VERSION 5.7 ;
BUSBITCHARS "[]" ;
DIVIDERCHAR "/" ;
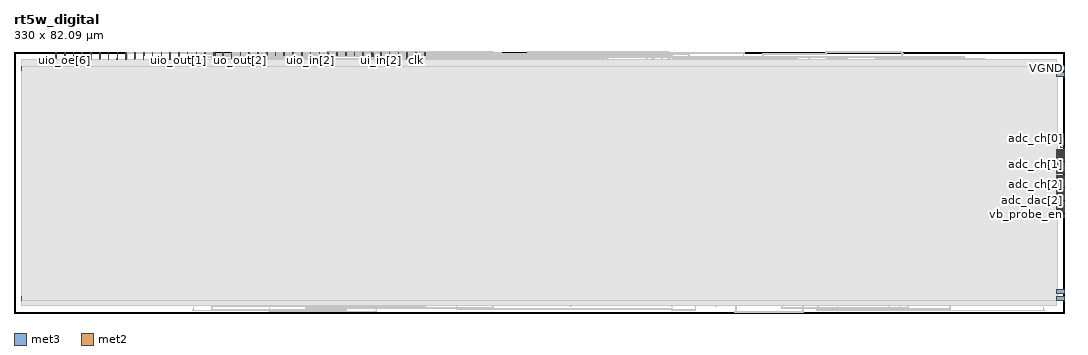
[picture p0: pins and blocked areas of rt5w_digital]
MACRO rt5w_digital
  CLASS BLOCK ;
  FOREIGN rt5w_digital ;
  ORIGIN 0.000 0.000 ;
  SIZE 330.000 BY 82.090 ;
  SYMMETRY X Y ;
  PIN VGND
    DIRECTION INOUT ;
    USE SIGNAL ;
    PORT
      LAYER met3 ;
        RECT 2.340 4.060 2.500 5.260 ;
        RECT 327.500 4.060 330.000 5.260 ;
        RECT 2.340 76.340 2.500 77.540 ;
        RECT 327.500 76.340 330.000 77.540 ;
    END
  END VGND
  PIN VPWR
    DIRECTION INOUT ;
    USE SIGNAL ;
    PORT
      LAYER met3 ;
        RECT 327.500 6.060 330.000 7.260 ;
        RECT 327.500 74.340 330.000 75.540 ;
    END
  END VPWR
  PIN adc_ch[0]
    DIRECTION INOUT ;
    USE SIGNAL ;
    PORT
      LAYER met3 ;
        RECT 329.050 51.870 330.000 52.170 ;
        RECT 328.750 51.870 329.050 52.850 ;
        RECT 327.500 54.590 329.670 54.890 ;
        RECT 329.670 52.850 329.970 54.890 ;
        RECT 329.050 52.550 329.970 52.850 ;
    END
  END adc_ch[0]
  PIN adc_ch[1]
    DIRECTION INOUT ;
    USE SIGNAL ;
    PORT
      LAYER met3 ;
        RECT 327.500 46.430 330.000 46.730 ;
    END
  END adc_ch[1]
  PIN adc_ch[2]
    DIRECTION INOUT ;
    USE SIGNAL ;
    PORT
      LAYER met3 ;
        RECT 327.500 40.310 330.000 40.610 ;
    END
  END adc_ch[2]
  PIN adc_ch[3]
    DIRECTION INOUT ;
    USE SIGNAL ;
    PORT
      LAYER met3 ;
        RECT 327.500 39.630 330.000 39.930 ;
    END
  END adc_ch[3]
  PIN adc_cmp
    DIRECTION INOUT ;
    USE SIGNAL ;
    PORT
      LAYER met3 ;
        RECT 327.500 40.990 330.000 41.290 ;
    END
  END adc_cmp
  PIN adc_dac[0]
    DIRECTION INOUT ;
    USE SIGNAL ;
    PORT
      LAYER met3 ;
        RECT 327.500 41.670 330.000 41.970 ;
    END
  END adc_dac[0]
  PIN adc_dac[1]
    DIRECTION INOUT ;
    USE SIGNAL ;
    PORT
      LAYER met3 ;
        RECT 327.500 47.110 330.000 47.410 ;
    END
  END adc_dac[1]
  PIN adc_dac[2]
    DIRECTION INOUT ;
    USE SIGNAL ;
    PORT
      LAYER met3 ;
        RECT 327.500 37.590 330.000 37.890 ;
    END
  END adc_dac[2]
  PIN adc_dac[3]
    DIRECTION INOUT ;
    USE SIGNAL ;
    PORT
      LAYER met3 ;
        RECT 327.500 36.910 330.000 37.210 ;
    END
  END adc_dac[3]
  PIN adc_dac[4]
    DIRECTION INOUT ;
    USE SIGNAL ;
    PORT
      LAYER met3 ;
        RECT 327.500 49.830 330.000 50.130 ;
    END
  END adc_dac[4]
  PIN adc_dac[5]
    DIRECTION INOUT ;
    USE SIGNAL ;
    PORT
      LAYER met3 ;
        RECT 327.500 36.230 330.000 36.530 ;
    END
  END adc_dac[5]
  PIN adc_dac[6]
    DIRECTION INOUT ;
    USE SIGNAL ;
    PORT
      LAYER met3 ;
        RECT 327.500 47.790 330.000 48.090 ;
    END
  END adc_dac[6]
  PIN adc_dac[7]
    DIRECTION INOUT ;
    USE SIGNAL ;
    PORT
      LAYER met3 ;
        RECT 327.500 34.870 330.000 35.170 ;
    END
  END adc_dac[7]
  PIN adc_lat
    DIRECTION INOUT ;
    USE SIGNAL ;
    PORT
      LAYER met3 ;
        RECT 327.500 43.030 330.000 43.330 ;
    END
  END adc_lat
  PIN adc_rst
    DIRECTION INOUT ;
    USE SIGNAL ;
    PORT
      LAYER met3 ;
        RECT 327.500 34.190 330.000 34.490 ;
    END
  END adc_rst
  PIN bias_en
    DIRECTION INOUT ;
    USE SIGNAL ;
    PORT
      LAYER met3 ;
        RECT 327.500 33.510 330.000 33.810 ;
    END
  END bias_en
  PIN cfg_sclk
    DIRECTION INOUT ;
    USE SIGNAL ;
    PORT
      LAYER met3 ;
        RECT 327.500 32.830 330.000 33.130 ;
    END
  END cfg_sclk
  PIN cfg_sdat
    DIRECTION INOUT ;
    USE SIGNAL ;
    PORT
      LAYER met3 ;
        RECT 327.500 43.710 330.000 44.010 ;
    END
  END cfg_sdat
  PIN clk
    DIRECTION INOUT ;
    USE SIGNAL ;
    PORT
      LAYER met2 ;
        RECT 126.240 81.000 126.340 82.000 ;
        RECT 126.270 79.800 126.340 81.000 ;
        RECT 126.200 79.590 126.340 79.800 ;
        RECT 126.340 79.660 126.410 81.000 ;
        RECT 126.340 81.000 126.440 82.000 ;
    END
  END clk
  PIN ena
    DIRECTION INOUT ;
    USE SIGNAL ;
    PORT
      LAYER met2 ;
        RECT 129.000 81.000 129.200 82.000 ;
    END
  END ena
  PIN pump_dn[0]
    DIRECTION INOUT ;
    USE SIGNAL ;
    PORT
      LAYER met3 ;
        RECT 327.500 48.470 330.000 48.770 ;
    END
  END pump_dn[0]
  PIN pump_dn[1]
    DIRECTION INOUT ;
    USE SIGNAL ;
    PORT
      LAYER met3 ;
        RECT 327.500 51.190 330.000 51.490 ;
    END
  END pump_dn[1]
  PIN pump_dn[2]
    DIRECTION INOUT ;
    USE SIGNAL ;
    PORT
      LAYER met3 ;
        RECT 327.500 38.270 330.000 38.570 ;
    END
  END pump_dn[2]
  PIN pump_dn[3]
    DIRECTION INOUT ;
    USE SIGNAL ;
    PORT
      LAYER met3 ;
        RECT 327.500 44.390 330.000 44.690 ;
    END
  END pump_dn[3]
  PIN pump_up[0]
    DIRECTION INOUT ;
    USE SIGNAL ;
    PORT
      LAYER met3 ;
        RECT 327.500 32.150 330.000 32.450 ;
    END
  END pump_up[0]
  PIN pump_up[1]
    DIRECTION INOUT ;
    USE SIGNAL ;
    PORT
      LAYER met3 ;
        RECT 327.500 50.510 330.000 50.810 ;
    END
  END pump_up[1]
  PIN pump_up[2]
    DIRECTION INOUT ;
    USE SIGNAL ;
    PORT
      LAYER met3 ;
        RECT 327.500 45.750 330.000 46.050 ;
    END
  END pump_up[2]
  PIN pump_up[3]
    DIRECTION INOUT ;
    USE SIGNAL ;
    PORT
      LAYER met3 ;
        RECT 327.500 45.070 330.000 45.370 ;
    END
  END pump_up[3]
  PIN rst_n
    DIRECTION INOUT ;
    USE SIGNAL ;
    PORT
      LAYER met2 ;
        RECT 123.480 81.000 123.580 82.000 ;
        RECT 123.510 79.800 123.580 81.000 ;
        RECT 123.440 79.590 123.580 79.800 ;
        RECT 123.580 79.660 123.650 81.000 ;
        RECT 123.580 81.000 123.680 82.000 ;
    END
  END rst_n
  PIN ui_in[0]
    DIRECTION INOUT ;
    USE SIGNAL ;
    PORT
      LAYER met2 ;
        RECT 120.720 81.000 120.820 82.000 ;
        RECT 120.750 79.800 120.820 81.000 ;
        RECT 120.680 79.590 120.820 79.800 ;
        RECT 120.820 79.660 120.890 81.000 ;
        RECT 120.820 81.000 120.920 82.000 ;
    END
  END ui_in[0]
  PIN ui_in[1]
    DIRECTION INOUT ;
    USE SIGNAL ;
    PORT
      LAYER met2 ;
        RECT 117.960 81.000 118.060 82.000 ;
        RECT 117.990 79.800 118.060 81.000 ;
        RECT 117.920 79.590 118.060 79.800 ;
        RECT 118.060 79.660 118.130 81.000 ;
        RECT 118.060 81.000 118.160 82.000 ;
    END
  END ui_in[1]
  PIN ui_in[2]
    DIRECTION INOUT ;
    USE SIGNAL ;
    PORT
      LAYER met2 ;
        RECT 115.200 81.000 115.300 82.000 ;
        RECT 115.230 79.800 115.300 81.000 ;
        RECT 115.160 79.590 115.300 79.800 ;
        RECT 115.300 79.660 115.370 81.000 ;
        RECT 115.300 81.000 115.400 82.000 ;
    END
  END ui_in[2]
  PIN ui_in[3]
    DIRECTION INOUT ;
    USE SIGNAL ;
    PORT
      LAYER met2 ;
        RECT 112.800 81.270 113.060 81.590 ;
        RECT 112.860 80.820 113.000 81.270 ;
        RECT 112.470 80.680 113.000 80.820 ;
        RECT 112.440 81.000 112.640 82.000 ;
        RECT 112.470 80.820 112.610 81.000 ;
    END
  END ui_in[3]
  PIN ui_in[4]
    DIRECTION INOUT ;
    USE SIGNAL ;
    PORT
      LAYER met2 ;
        RECT 109.680 81.000 109.880 82.000 ;
    END
  END ui_in[4]
  PIN ui_in[5]
    DIRECTION INOUT ;
    USE SIGNAL ;
    PORT
      LAYER met2 ;
        RECT 106.920 81.000 107.120 82.000 ;
    END
  END ui_in[5]
  PIN ui_in[6]
    DIRECTION INOUT ;
    USE SIGNAL ;
    PORT
      LAYER met2 ;
        RECT 104.160 81.000 104.360 82.000 ;
    END
  END ui_in[6]
  PIN ui_in[7]
    DIRECTION INOUT ;
    USE SIGNAL ;
    PORT
      LAYER met2 ;
        RECT 101.400 81.000 101.600 82.000 ;
    END
  END ui_in[7]
  PIN uio_in[0]
    DIRECTION INOUT ;
    USE SIGNAL ;
    PORT
      LAYER met2 ;
        RECT 98.640 81.000 98.840 82.000 ;
    END
  END uio_in[0]
  PIN uio_in[1]
    DIRECTION INOUT ;
    USE SIGNAL ;
    PORT
      LAYER met2 ;
        RECT 95.880 81.000 96.080 82.000 ;
    END
  END uio_in[1]
  PIN uio_in[2]
    DIRECTION INOUT ;
    USE SIGNAL ;
    PORT
      LAYER met2 ;
        RECT 93.120 81.000 93.320 82.000 ;
    END
  END uio_in[2]
  PIN uio_in[3]
    DIRECTION INOUT ;
    USE SIGNAL ;
    PORT
      LAYER met2 ;
        RECT 90.360 81.000 90.560 82.000 ;
    END
  END uio_in[3]
  PIN uio_in[4]
    DIRECTION INOUT ;
    USE SIGNAL ;
    PORT
      LAYER met2 ;
        RECT 87.600 81.000 87.800 82.000 ;
    END
  END uio_in[4]
  PIN uio_in[5]
    DIRECTION INOUT ;
    USE SIGNAL ;
    PORT
      LAYER met2 ;
        RECT 84.840 81.000 85.040 82.000 ;
    END
  END uio_in[5]
  PIN uio_in[6]
    DIRECTION INOUT ;
    USE SIGNAL ;
    PORT
      LAYER met2 ;
        RECT 82.080 81.000 82.280 82.000 ;
    END
  END uio_in[6]
  PIN uio_in[7]
    DIRECTION INOUT ;
    USE SIGNAL ;
    PORT
      LAYER met2 ;
        RECT 79.320 81.000 79.520 82.000 ;
    END
  END uio_in[7]
  PIN uio_oe[0]
    DIRECTION INOUT ;
    USE SIGNAL ;
    PORT
      LAYER met2 ;
        RECT 32.400 81.000 32.500 82.000 ;
        RECT 32.430 79.970 32.500 81.000 ;
        RECT 32.360 79.590 32.500 79.970 ;
        RECT 32.500 79.830 32.570 81.000 ;
        RECT 32.500 81.000 32.600 82.000 ;
    END
  END uio_oe[0]
  PIN uio_oe[1]
    DIRECTION INOUT ;
    USE SIGNAL ;
    PORT
      LAYER met2 ;
        RECT 29.640 81.000 29.740 82.000 ;
        RECT 29.670 79.970 29.740 81.000 ;
        RECT 29.600 79.590 29.740 79.970 ;
        RECT 29.740 79.830 29.810 81.000 ;
        RECT 29.740 81.000 29.840 82.000 ;
    END
  END uio_oe[1]
  PIN uio_oe[2]
    DIRECTION INOUT ;
    USE SIGNAL ;
    PORT
      LAYER met2 ;
        RECT 26.880 81.000 26.980 82.000 ;
        RECT 26.910 79.970 26.980 81.000 ;
        RECT 26.840 79.590 26.980 79.970 ;
        RECT 26.980 79.830 27.050 81.000 ;
        RECT 26.980 81.000 27.080 82.000 ;
    END
  END uio_oe[2]
  PIN uio_oe[3]
    DIRECTION INOUT ;
    USE SIGNAL ;
    PORT
      LAYER met2 ;
        RECT 24.120 81.000 24.220 82.000 ;
        RECT 24.150 79.970 24.220 81.000 ;
        RECT 24.080 79.590 24.220 79.970 ;
        RECT 24.220 79.830 24.290 81.000 ;
        RECT 24.220 81.000 24.320 82.000 ;
    END
  END uio_oe[3]
  PIN uio_oe[4]
    DIRECTION INOUT ;
    USE SIGNAL ;
    PORT
      LAYER met2 ;
        RECT 21.360 81.000 21.460 82.000 ;
        RECT 21.390 79.970 21.460 81.000 ;
        RECT 21.320 79.590 21.460 79.970 ;
        RECT 21.460 79.830 21.530 81.000 ;
        RECT 21.460 81.000 21.560 82.000 ;
    END
  END uio_oe[4]
  PIN uio_oe[5]
    DIRECTION INOUT ;
    USE SIGNAL ;
    PORT
      LAYER met2 ;
        RECT 18.600 81.000 18.700 82.000 ;
        RECT 18.630 79.970 18.700 81.000 ;
        RECT 18.560 79.590 18.700 79.970 ;
        RECT 18.700 79.830 18.770 81.000 ;
        RECT 18.700 81.000 18.800 82.000 ;
    END
  END uio_oe[5]
  PIN uio_oe[6]
    DIRECTION INOUT ;
    USE SIGNAL ;
    PORT
      LAYER met2 ;
        RECT 15.840 81.000 15.940 82.000 ;
        RECT 15.870 79.970 15.940 81.000 ;
        RECT 15.800 79.590 15.940 79.970 ;
        RECT 15.940 79.830 16.010 81.000 ;
        RECT 15.940 81.000 16.040 82.000 ;
    END
  END uio_oe[6]
  PIN uio_oe[7]
    DIRECTION INOUT ;
    USE SIGNAL ;
    PORT
      LAYER met2 ;
        RECT 13.080 81.000 13.180 82.000 ;
        RECT 13.110 79.970 13.180 81.000 ;
        RECT 13.040 79.590 13.180 79.970 ;
        RECT 13.180 79.830 13.250 81.000 ;
        RECT 13.180 81.000 13.280 82.000 ;
    END
  END uio_oe[7]
  PIN uio_out[0]
    DIRECTION INOUT ;
    USE SIGNAL ;
    PORT
      LAYER met2 ;
        RECT 54.480 81.000 54.580 82.000 ;
        RECT 54.510 79.800 54.580 81.000 ;
        RECT 54.440 79.590 54.580 79.800 ;
        RECT 54.580 79.660 54.650 81.000 ;
        RECT 54.580 81.000 54.680 82.000 ;
    END
  END uio_out[0]
  PIN uio_out[1]
    DIRECTION INOUT ;
    USE SIGNAL ;
    PORT
      LAYER met2 ;
        RECT 51.720 81.000 51.820 82.000 ;
        RECT 51.750 79.970 51.820 81.000 ;
        RECT 51.680 79.590 51.820 79.970 ;
        RECT 51.820 79.830 51.890 81.000 ;
        RECT 51.820 81.000 51.920 82.000 ;
    END
  END uio_out[1]
  PIN uio_out[2]
    DIRECTION INOUT ;
    USE SIGNAL ;
    PORT
      LAYER met2 ;
        RECT 48.960 81.000 49.060 82.000 ;
        RECT 48.990 79.970 49.060 81.000 ;
        RECT 48.920 79.590 49.060 79.970 ;
        RECT 49.060 79.830 49.130 81.000 ;
        RECT 49.060 81.000 49.160 82.000 ;
    END
  END uio_out[2]
  PIN uio_out[3]
    DIRECTION INOUT ;
    USE SIGNAL ;
    PORT
      LAYER met2 ;
        RECT 46.200 81.000 46.300 82.000 ;
        RECT 46.230 79.970 46.300 81.000 ;
        RECT 46.160 79.590 46.300 79.970 ;
        RECT 46.300 79.830 46.370 81.000 ;
        RECT 46.300 81.000 46.400 82.000 ;
    END
  END uio_out[3]
  PIN uio_out[4]
    DIRECTION INOUT ;
    USE SIGNAL ;
    PORT
      LAYER met2 ;
        RECT 43.440 81.000 43.540 82.000 ;
        RECT 43.470 79.970 43.540 81.000 ;
        RECT 43.400 79.590 43.540 79.970 ;
        RECT 43.540 79.830 43.610 81.000 ;
        RECT 43.540 81.000 43.640 82.000 ;
    END
  END uio_out[4]
  PIN uio_out[5]
    DIRECTION INOUT ;
    USE SIGNAL ;
    PORT
      LAYER met2 ;
        RECT 40.680 81.000 40.780 82.000 ;
        RECT 40.710 79.970 40.780 81.000 ;
        RECT 40.640 79.590 40.780 79.970 ;
        RECT 40.780 79.830 40.850 81.000 ;
        RECT 40.780 81.000 40.880 82.000 ;
    END
  END uio_out[5]
  PIN uio_out[6]
    DIRECTION INOUT ;
    USE SIGNAL ;
    PORT
      LAYER met2 ;
        RECT 37.920 81.000 38.020 82.000 ;
        RECT 37.950 79.970 38.020 81.000 ;
        RECT 37.880 79.590 38.020 79.970 ;
        RECT 38.020 79.830 38.090 81.000 ;
        RECT 38.020 81.000 38.120 82.000 ;
    END
  END uio_out[6]
  PIN uio_out[7]
    DIRECTION INOUT ;
    USE SIGNAL ;
    PORT
      LAYER met2 ;
        RECT 35.160 81.000 35.260 82.000 ;
        RECT 35.190 79.970 35.260 81.000 ;
        RECT 35.120 79.590 35.260 79.970 ;
        RECT 35.260 79.830 35.330 81.000 ;
        RECT 35.260 81.000 35.360 82.000 ;
    END
  END uio_out[7]
  PIN uo_out[0]
    DIRECTION INOUT ;
    USE SIGNAL ;
    PORT
      LAYER met2 ;
        RECT 76.560 81.000 76.660 82.000 ;
        RECT 76.590 79.800 76.660 81.000 ;
        RECT 76.520 79.590 76.660 79.800 ;
        RECT 76.660 79.660 76.730 81.000 ;
        RECT 76.660 81.000 76.760 82.000 ;
    END
  END uo_out[0]
  PIN uo_out[1]
    DIRECTION INOUT ;
    USE SIGNAL ;
    PORT
      LAYER met2 ;
        RECT 73.800 81.000 74.000 82.000 ;
        RECT 73.830 80.765 73.970 81.000 ;
        RECT 73.760 80.395 74.040 80.765 ;
    END
  END uo_out[1]
  PIN uo_out[2]
    DIRECTION INOUT ;
    USE SIGNAL ;
    PORT
      LAYER met2 ;
        RECT 71.040 81.000 71.140 82.000 ;
        RECT 71.070 79.800 71.140 81.000 ;
        RECT 71.000 79.590 71.140 79.800 ;
        RECT 71.140 79.660 71.210 81.000 ;
        RECT 71.140 81.000 71.240 82.000 ;
    END
  END uo_out[2]
  PIN uo_out[3]
    DIRECTION INOUT ;
    USE SIGNAL ;
    PORT
      LAYER met2 ;
        RECT 68.280 81.000 68.480 82.000 ;
        RECT 68.310 80.230 68.450 81.000 ;
        RECT 68.250 79.910 68.510 80.230 ;
    END
  END uo_out[3]
  PIN uo_out[4]
    DIRECTION INOUT ;
    USE SIGNAL ;
    PORT
      LAYER met2 ;
        RECT 65.520 81.000 65.720 82.000 ;
        RECT 65.550 80.085 65.690 81.000 ;
        RECT 65.480 79.715 65.760 80.085 ;
    END
  END uo_out[4]
  PIN uo_out[5]
    DIRECTION INOUT ;
    USE SIGNAL ;
    PORT
      LAYER met2 ;
        RECT 63.120 81.270 63.380 81.590 ;
        RECT 63.180 80.650 63.320 81.270 ;
        RECT 62.790 80.510 63.320 80.650 ;
        RECT 62.760 81.000 62.960 82.000 ;
        RECT 62.790 80.650 62.930 81.000 ;
    END
  END uo_out[5]
  PIN uo_out[6]
    DIRECTION INOUT ;
    USE SIGNAL ;
    PORT
      LAYER met2 ;
        RECT 60.000 81.000 60.200 82.000 ;
        RECT 60.030 80.570 60.170 81.000 ;
        RECT 59.970 80.250 60.230 80.570 ;
    END
  END uo_out[6]
  PIN uo_out[7]
    DIRECTION INOUT ;
    USE SIGNAL ;
    PORT
      LAYER met2 ;
        RECT 57.240 81.000 57.340 82.000 ;
        RECT 57.270 79.970 57.340 81.000 ;
        RECT 57.200 79.590 57.340 79.970 ;
        RECT 57.340 79.830 57.410 81.000 ;
        RECT 57.340 81.000 57.440 82.000 ;
    END
  END uo_out[7]
  PIN vb_probe_en
    DIRECTION INOUT ;
    USE SIGNAL ;
    PORT
      LAYER met3 ;
        RECT 327.500 30.790 330.000 31.090 ;
    END
  END vb_probe_en
  PIN wsel_a[0]
    DIRECTION INOUT ;
    USE SIGNAL ;
    PORT
      LAYER met3 ;
        RECT 327.500 30.110 330.000 30.410 ;
    END
  END wsel_a[0]
  PIN wsel_a[1]
    DIRECTION INOUT ;
    USE SIGNAL ;
    PORT
      LAYER met3 ;
        RECT 327.500 42.350 330.000 42.650 ;
    END
  END wsel_a[1]
  PIN wsel_a[2]
    DIRECTION INOUT ;
    USE SIGNAL ;
    PORT
      LAYER met3 ;
        RECT 327.500 49.150 330.000 49.450 ;
    END
  END wsel_a[2]
  PIN wsel_a[3]
    DIRECTION INOUT ;
    USE SIGNAL ;
    PORT
      LAYER met3 ;
        RECT 327.500 31.470 330.000 31.770 ;
    END
  END wsel_a[3]
  PIN wsel_a[4]
    DIRECTION INOUT ;
    USE SIGNAL ;
    PORT
      LAYER met3 ;
        RECT 327.500 38.950 330.000 39.250 ;
    END
  END wsel_a[4]
  PIN wsel_e
    DIRECTION INOUT ;
    USE SIGNAL ;
    PORT
      LAYER met3 ;
        RECT 327.500 35.550 330.000 35.850 ;
    END
  END wsel_e
  OBS
    LAYER li1 ;
      RECT 2.500 2.500 327.500 79.590 ;
    LAYER met1 ;
      RECT 138.990 1.120 206.610 1.260 ;
      RECT 132.550 79.660 173.030 79.800 ;
      RECT 134.390 80.000 182.690 80.140 ;
      RECT 2.500 2.500 327.500 79.590 ;
      RECT 153.110 80.340 217.280 80.480 ;
      RECT 85.630 81.020 200.170 81.160 ;
      RECT 112.770 81.360 201.090 81.500 ;
      RECT 173.030 79.600 173.350 79.860 ;
      RECT 182.690 79.940 183.010 80.200 ;
      RECT 173.490 79.600 173.810 79.660 ;
      RECT 217.280 80.000 241.570 80.140 ;
      RECT 241.570 79.940 241.890 80.200 ;
      RECT 173.490 79.800 173.810 79.860 ;
      RECT 217.280 80.140 217.420 80.480 ;
      RECT 234.670 80.280 234.990 80.340 ;
      RECT 234.670 80.480 234.990 80.540 ;
      RECT 234.670 80.340 255.370 80.480 ;
      RECT 255.370 80.280 255.690 80.540 ;
      RECT 165.210 80.620 165.530 80.680 ;
      RECT 165.210 80.820 165.530 80.880 ;
      RECT 165.210 80.680 205.230 80.820 ;
      RECT 205.230 80.620 205.550 80.880 ;
      RECT 173.490 79.660 203.390 79.800 ;
      RECT 200.170 80.960 200.490 81.220 ;
      RECT 200.630 80.960 200.950 81.020 ;
      RECT 200.630 81.160 200.950 81.220 ;
      RECT 200.630 81.020 205.690 81.160 ;
      RECT 205.690 80.960 206.010 81.220 ;
      RECT 203.390 79.600 203.710 79.860 ;
      RECT 201.090 81.300 201.410 81.560 ;
      RECT 202.010 81.300 202.330 81.360 ;
      RECT 202.010 81.500 202.330 81.560 ;
      RECT 202.010 81.360 206.150 81.500 ;
      RECT 206.150 81.300 206.470 81.560 ;
      RECT 188.210 81.640 188.530 81.700 ;
      RECT 188.210 81.840 188.530 81.900 ;
      RECT 188.210 81.700 229.150 81.840 ;
      RECT 229.150 81.640 229.470 81.900 ;
      RECT 87.930 80.340 98.050 80.480 ;
      RECT 98.050 80.280 98.370 80.540 ;
      RECT 111.850 80.280 112.170 80.340 ;
      RECT 111.850 80.480 112.170 80.540 ;
      RECT 111.850 80.340 127.030 80.480 ;
      RECT 127.030 80.280 127.350 80.540 ;
      RECT 127.490 80.280 127.810 80.340 ;
      RECT 127.490 80.480 127.810 80.540 ;
      RECT 127.490 80.340 129.790 80.480 ;
      RECT 129.790 80.280 130.110 80.540 ;
      RECT 68.220 80.140 68.540 80.200 ;
      RECT 131.260 80.000 131.400 80.340 ;
      RECT 68.220 79.940 68.540 80.140 ;
      RECT 68.540 80.000 131.260 80.140 ;
      RECT 131.260 80.340 152.330 80.480 ;
      RECT 152.330 80.280 152.650 80.540 ;
      RECT 132.550 79.800 132.870 79.860 ;
      RECT 82.410 79.600 82.730 79.660 ;
      RECT 152.790 80.280 153.110 80.340 ;
      RECT 82.410 79.800 82.730 79.860 ;
      RECT 152.790 80.340 153.110 80.540 ;
      RECT 82.410 79.660 106.330 79.800 ;
      RECT 106.330 79.600 106.650 79.860 ;
      RECT 106.790 79.600 107.110 79.660 ;
      RECT 106.790 79.800 107.110 79.860 ;
      RECT 112.310 79.800 112.630 79.860 ;
      RECT 110.010 80.620 110.330 80.680 ;
      RECT 110.010 80.820 110.330 80.880 ;
      RECT 110.010 80.680 160.150 80.820 ;
      RECT 160.150 80.620 160.470 80.880 ;
      RECT 132.220 79.660 132.360 80.000 ;
      RECT 112.310 79.600 112.630 79.800 ;
      RECT 112.630 79.660 132.220 79.800 ;
      RECT 132.220 80.000 133.930 80.140 ;
      RECT 85.630 80.960 85.950 81.020 ;
      RECT 85.630 81.160 85.950 81.220 ;
      RECT 133.930 79.940 134.250 80.200 ;
      RECT 134.390 79.940 134.710 80.000 ;
      RECT 134.390 80.140 134.710 80.200 ;
      RECT 106.790 79.660 110.010 79.800 ;
      RECT 110.010 79.600 110.330 79.860 ;
      RECT 59.940 80.280 60.260 80.340 ;
      RECT 57.570 81.300 57.890 81.360 ;
      RECT 57.570 81.500 57.890 81.560 ;
      RECT 57.570 81.360 62.170 81.500 ;
      RECT 62.170 81.300 62.490 81.560 ;
      RECT 63.090 81.300 63.410 81.360 ;
      RECT 63.090 81.500 63.410 81.560 ;
      RECT 63.090 81.360 111.850 81.500 ;
      RECT 111.850 81.300 112.170 81.560 ;
      RECT 112.770 81.300 113.090 81.360 ;
      RECT 112.770 81.500 113.090 81.560 ;
      RECT 60.260 80.340 62.025 80.480 ;
      RECT 59.940 80.340 60.260 80.540 ;
      RECT 62.025 79.590 62.165 80.480 ;
      RECT 132.550 79.600 132.870 79.660 ;
      RECT 75.970 80.280 76.290 80.340 ;
      RECT 75.970 80.480 76.290 80.540 ;
      RECT 62.790 80.680 109.090 80.820 ;
      RECT 109.090 80.620 109.410 80.880 ;
      RECT 35.490 81.640 35.810 81.700 ;
      RECT 35.810 81.700 62.790 81.840 ;
      RECT 35.490 81.700 35.810 81.900 ;
      RECT 62.790 80.820 62.930 81.840 ;
      RECT 68.610 81.640 68.930 81.700 ;
      RECT 68.610 81.840 68.930 81.900 ;
      RECT 68.610 81.700 88.850 81.840 ;
      RECT 88.850 81.640 89.170 81.900 ;
      RECT 89.310 81.640 89.630 81.700 ;
      RECT 89.310 81.840 89.630 81.900 ;
      RECT 89.310 81.700 132.550 81.840 ;
      RECT 132.550 81.640 132.870 81.900 ;
      RECT 133.010 81.640 133.330 81.700 ;
      RECT 133.010 81.840 133.330 81.900 ;
      RECT 133.010 81.700 152.790 81.840 ;
      RECT 152.790 81.640 153.110 81.900 ;
      RECT 75.970 80.340 86.550 80.480 ;
      RECT 86.550 80.280 86.870 80.540 ;
      RECT 87.930 80.280 88.250 80.340 ;
      RECT 87.930 80.480 88.250 80.540 ;
      RECT 56.190 0.920 56.510 0.980 ;
      RECT 56.190 0.780 96.670 0.920 ;
      RECT 96.670 0.720 96.990 0.980 ;
      RECT 138.990 1.060 139.310 1.120 ;
      RECT 138.990 1.260 139.310 1.320 ;
      RECT 80.110 0.380 80.430 0.440 ;
      RECT 62.170 2.080 62.490 2.140 ;
      RECT 62.170 2.280 62.490 2.340 ;
      RECT 85.170 2.420 85.490 2.480 ;
      RECT 62.170 2.140 128.870 2.280 ;
      RECT 85.170 2.480 138.530 2.500 ;
      RECT 138.530 2.420 138.850 2.500 ;
      RECT 128.870 2.080 129.190 2.340 ;
      RECT 80.110 0.580 80.430 0.640 ;
      RECT 80.110 0.440 113.690 0.580 ;
      RECT 113.690 0.380 114.010 0.640 ;
      RECT 56.190 0.720 56.510 0.780 ;
      RECT 258.590 1.120 294.010 1.260 ;
      RECT 294.010 1.060 294.330 1.320 ;
      RECT 323.450 0.720 323.770 0.980 ;
      RECT 274.690 0.720 275.010 0.780 ;
      RECT 274.690 0.920 275.010 0.980 ;
      RECT 274.690 0.780 323.450 0.920 ;
      RECT 206.610 1.060 206.930 1.320 ;
      RECT 258.590 1.060 258.910 1.120 ;
      RECT 258.590 1.260 258.910 1.320 ;
    LAYER met2 ;
      RECT 2.500 2.500 327.500 79.590 ;
      RECT 255.460 80.085 255.600 80.250 ;
      RECT 255.390 79.715 255.670 80.085 ;
      RECT 173.520 79.590 173.780 79.890 ;
      RECT 203.420 79.590 203.680 79.890 ;
      RECT 182.720 79.910 182.980 80.230 ;
      RECT 182.780 79.590 182.920 79.910 ;
      RECT 241.600 79.910 241.860 80.230 ;
      RECT 241.660 79.590 241.800 79.910 ;
      RECT 173.120 79.890 173.260 80.510 ;
      RECT 173.060 79.590 173.320 79.890 ;
      RECT 234.700 80.250 234.960 80.570 ;
      RECT 234.760 79.590 234.900 80.250 ;
      RECT 173.120 80.510 174.500 80.650 ;
      RECT 174.500 79.590 174.640 80.650 ;
      RECT 244.350 80.395 244.630 80.765 ;
      RECT 244.420 79.590 244.560 80.395 ;
      RECT 255.400 80.250 255.660 80.570 ;
      RECT 165.240 80.590 165.500 80.910 ;
      RECT 165.300 79.590 165.440 80.590 ;
      RECT 205.260 80.590 205.520 80.910 ;
      RECT 205.320 79.590 205.460 80.590 ;
      RECT 181.790 81.075 182.070 81.190 ;
      RECT 200.200 80.930 200.460 81.250 ;
      RECT 200.260 79.590 200.400 80.930 ;
      RECT 200.660 80.930 200.920 81.250 ;
      RECT 200.720 79.590 200.860 80.930 ;
      RECT 205.720 80.930 205.980 81.250 ;
      RECT 205.780 79.590 205.920 80.930 ;
      RECT 182.070 81.190 182.460 81.330 ;
      RECT 182.320 79.590 182.460 81.190 ;
      RECT 181.790 81.190 182.070 81.445 ;
      RECT 235.150 81.075 235.430 81.445 ;
      RECT 235.220 79.590 235.360 81.075 ;
      RECT 201.120 81.270 201.380 81.590 ;
      RECT 201.180 79.590 201.320 81.270 ;
      RECT 206.180 81.270 206.440 81.590 ;
      RECT 206.240 79.590 206.380 81.270 ;
      RECT 198.880 79.590 199.020 81.870 ;
      RECT 188.240 81.610 188.500 81.930 ;
      RECT 188.300 79.590 188.440 81.610 ;
      RECT 229.180 81.610 229.440 81.930 ;
      RECT 229.240 79.590 229.380 81.610 ;
      RECT 198.880 81.870 202.100 82.010 ;
      RECT 202.100 81.590 202.240 82.010 ;
      RECT 202.040 81.270 202.300 81.590 ;
      RECT 204.860 81.445 205.000 81.870 ;
      RECT 204.790 81.075 205.070 81.445 ;
      RECT 204.860 81.870 206.700 82.010 ;
      RECT 206.700 81.445 206.840 82.010 ;
      RECT 206.630 81.075 206.910 81.445 ;
      RECT 127.520 80.250 127.780 80.395 ;
      RECT 133.950 80.395 134.230 80.765 ;
      RECT 134.020 80.230 134.160 80.395 ;
      RECT 133.960 79.910 134.220 80.230 ;
      RECT 76.000 80.250 76.260 80.570 ;
      RECT 76.060 79.590 76.200 80.250 ;
      RECT 86.580 80.250 86.840 80.570 ;
      RECT 86.640 79.590 86.780 80.250 ;
      RECT 127.260 79.830 128.500 79.970 ;
      RECT 128.500 79.590 128.640 79.970 ;
      RECT 127.060 80.250 127.320 80.570 ;
      RECT 127.120 79.830 127.260 80.250 ;
      RECT 152.360 80.250 152.620 80.570 ;
      RECT 152.420 79.590 152.560 80.250 ;
      RECT 109.120 80.765 109.380 80.910 ;
      RECT 109.110 80.395 109.390 80.765 ;
      RECT 85.650 81.075 85.930 81.445 ;
      RECT 85.660 80.930 85.920 81.075 ;
      RECT 58.050 80.395 58.330 80.765 ;
      RECT 58.120 79.590 58.260 80.395 ;
      RECT 118.310 80.395 118.590 80.765 ;
      RECT 118.380 79.590 118.520 80.395 ;
      RECT 132.110 80.395 132.390 80.765 ;
      RECT 132.180 79.590 132.320 80.395 ;
      RECT 98.070 81.075 98.350 81.445 ;
      RECT 98.140 80.570 98.280 81.075 ;
      RECT 98.080 80.250 98.340 80.570 ;
      RECT 109.640 79.800 109.780 80.510 ;
      RECT 109.180 79.590 109.320 79.800 ;
      RECT 109.320 79.660 109.780 79.800 ;
      RECT 110.040 80.650 110.300 80.910 ;
      RECT 109.640 80.510 110.240 80.590 ;
      RECT 109.640 80.590 110.300 80.650 ;
      RECT 160.180 80.590 160.440 80.910 ;
      RECT 160.240 79.590 160.380 80.590 ;
      RECT 129.810 81.075 130.090 81.445 ;
      RECT 129.880 80.570 130.020 81.075 ;
      RECT 129.820 80.250 130.080 80.570 ;
      RECT 111.880 81.270 112.140 81.590 ;
      RECT 111.940 80.570 112.080 81.270 ;
      RECT 111.880 80.250 112.140 80.570 ;
      RECT 88.880 81.610 89.140 81.930 ;
      RECT 88.940 80.085 89.080 81.610 ;
      RECT 88.870 79.715 89.150 80.085 ;
      RECT 89.340 81.610 89.600 81.930 ;
      RECT 89.400 80.765 89.540 81.610 ;
      RECT 131.190 81.075 131.470 81.445 ;
      RECT 131.260 79.590 131.400 81.075 ;
      RECT 150.510 81.075 150.790 81.445 ;
      RECT 150.580 79.590 150.720 81.075 ;
      RECT 161.550 81.075 161.830 81.445 ;
      RECT 161.620 79.590 161.760 81.075 ;
      RECT 89.330 80.395 89.610 80.765 ;
      RECT 152.820 81.610 153.080 81.930 ;
      RECT 152.880 80.570 153.020 81.610 ;
      RECT 152.820 80.250 153.080 80.570 ;
      RECT 82.440 79.590 82.700 79.890 ;
      RECT 57.600 81.270 57.860 81.590 ;
      RECT 57.660 79.590 57.800 81.270 ;
      RECT 62.200 81.270 62.460 81.590 ;
      RECT 62.260 79.590 62.400 81.270 ;
      RECT 106.360 79.590 106.620 79.890 ;
      RECT 110.040 79.590 110.300 79.890 ;
      RECT 112.340 79.590 112.600 79.890 ;
      RECT 87.960 80.250 88.220 80.570 ;
      RECT 88.020 80.085 88.160 80.250 ;
      RECT 35.520 81.610 35.780 81.930 ;
      RECT 35.580 79.590 35.720 81.610 ;
      RECT 68.640 81.610 68.900 81.930 ;
      RECT 68.700 79.590 68.840 81.610 ;
      RECT 132.580 81.610 132.840 81.930 ;
      RECT 132.640 79.890 132.780 81.610 ;
      RECT 132.580 79.590 132.840 79.890 ;
      RECT 133.040 81.610 133.300 81.930 ;
      RECT 133.100 79.590 133.240 81.610 ;
      RECT 106.810 79.715 107.090 80.085 ;
      RECT 106.820 79.590 107.080 79.715 ;
      RECT 120.150 79.715 120.430 80.085 ;
      RECT 120.220 79.590 120.360 79.715 ;
      RECT 139.470 79.715 139.750 80.085 ;
      RECT 139.540 79.590 139.680 79.715 ;
      RECT 146.830 79.715 147.110 80.085 ;
      RECT 146.900 79.590 147.040 79.715 ;
      RECT 134.420 79.910 134.680 80.230 ;
      RECT 134.480 79.590 134.620 79.910 ;
      RECT 87.950 79.715 88.230 80.085 ;
      RECT 127.510 80.395 127.790 80.765 ;
      RECT 138.560 2.390 138.820 2.500 ;
      RECT 139.080 1.350 139.220 2.500 ;
      RECT 139.020 1.030 139.280 1.350 ;
      RECT 56.280 1.010 56.420 2.500 ;
      RECT 56.220 0.690 56.480 1.010 ;
      RECT 62.260 2.370 62.400 2.500 ;
      RECT 62.200 2.050 62.460 2.370 ;
      RECT 80.200 0.670 80.340 2.500 ;
      RECT 80.140 0.350 80.400 0.670 ;
      RECT 85.200 2.390 85.460 2.500 ;
      RECT 91.700 1.885 91.840 2.500 ;
      RECT 91.630 1.515 91.910 1.885 ;
      RECT 93.470 2.195 93.750 2.500 ;
      RECT 96.760 1.010 96.900 2.500 ;
      RECT 96.700 0.690 96.960 1.010 ;
      RECT 104.120 1.205 104.260 2.500 ;
      RECT 104.050 0.835 104.330 1.205 ;
      RECT 113.780 0.670 113.920 2.500 ;
      RECT 113.720 0.350 113.980 0.670 ;
      RECT 116.930 2.450 117.210 2.500 ;
      RECT 116.930 2.195 117.210 2.450 ;
      RECT 117.460 2.310 117.600 2.500 ;
      RECT 117.210 2.310 117.460 2.450 ;
      RECT 124.820 1.885 124.960 2.500 ;
      RECT 124.750 1.515 125.030 1.885 ;
      RECT 128.960 2.370 129.100 2.500 ;
      RECT 128.900 2.050 129.160 2.370 ;
      RECT 220.430 2.195 220.710 2.500 ;
      RECT 258.680 1.350 258.820 2.500 ;
      RECT 258.620 1.030 258.880 1.350 ;
      RECT 274.780 1.010 274.920 2.500 ;
      RECT 274.720 0.690 274.980 1.010 ;
      RECT 294.100 1.350 294.240 2.500 ;
      RECT 294.040 1.030 294.300 1.350 ;
      RECT 206.640 1.205 206.900 1.350 ;
      RECT 206.630 0.835 206.910 1.205 ;
      RECT 174.890 2.195 175.170 2.500 ;
      RECT 206.630 2.195 206.910 2.500 ;
      RECT 214.060 1.205 214.200 2.500 ;
      RECT 213.990 0.835 214.270 1.205 ;
      RECT 323.540 1.010 323.680 2.500 ;
      RECT 323.480 0.690 323.740 1.010 ;
    LAYER met3 ;
      RECT 137.350 2.230 174.865 2.500 ;
      RECT 2.500 2.500 327.500 79.590 ;
      RECT 146.805 79.750 185.190 80.050 ;
      RECT 162.190 81.110 181.765 81.410 ;
      RECT 152.450 80.430 182.700 80.730 ;
      RECT 161.540 81.790 205.470 82.090 ;
      RECT 270.750 80.050 271.130 80.060 ;
      RECT 270.750 79.750 304.790 80.050 ;
      RECT 304.790 79.740 305.170 80.060 ;
      RECT 206.845 79.590 207.145 79.750 ;
      RECT 185.190 79.740 185.570 80.060 ;
      RECT 255.365 79.735 255.695 79.750 ;
      RECT 255.365 79.750 261.550 80.050 ;
      RECT 261.550 79.740 261.930 80.060 ;
      RECT 255.365 80.050 255.695 80.065 ;
      RECT 249.590 80.420 249.970 80.430 ;
      RECT 249.590 80.730 249.970 80.740 ;
      RECT 249.590 80.430 298.350 80.730 ;
      RECT 298.350 80.420 298.730 80.740 ;
      RECT 186.110 80.420 186.490 80.430 ;
      RECT 186.110 80.730 186.490 80.740 ;
      RECT 186.110 80.430 244.325 80.730 ;
      RECT 244.325 80.415 244.655 80.745 ;
      RECT 206.845 79.750 245.910 80.050 ;
      RECT 181.765 81.095 182.095 81.425 ;
      RECT 182.700 80.430 183.000 81.110 ;
      RECT 245.910 79.740 246.290 80.060 ;
      RECT 182.700 81.110 204.765 81.410 ;
      RECT 204.765 81.095 205.095 81.425 ;
      RECT 206.605 81.095 206.935 81.110 ;
      RECT 206.605 81.110 211.870 81.410 ;
      RECT 211.870 81.100 212.250 81.420 ;
      RECT 206.605 81.410 206.935 81.425 ;
      RECT 270.750 79.740 271.130 79.750 ;
      RECT 205.470 81.420 205.770 82.090 ;
      RECT 205.430 81.100 205.810 81.420 ;
      RECT 235.125 81.410 235.455 81.425 ;
      RECT 255.145 81.110 255.445 81.790 ;
      RECT 235.125 81.095 235.455 81.410 ;
      RECT 235.455 81.110 255.145 81.410 ;
      RECT 255.145 81.790 279.070 82.090 ;
      RECT 279.070 81.420 279.370 82.090 ;
      RECT 279.030 81.100 279.410 81.420 ;
      RECT 118.285 80.430 127.485 80.730 ;
      RECT 127.485 80.415 127.815 80.745 ;
      RECT 133.925 80.415 134.255 80.430 ;
      RECT 133.925 80.430 143.790 80.730 ;
      RECT 143.790 80.420 144.170 80.740 ;
      RECT 133.925 80.730 134.255 80.745 ;
      RECT 120.125 79.750 139.445 80.050 ;
      RECT 139.445 79.735 139.775 80.065 ;
      RECT 146.805 79.735 147.135 79.750 ;
      RECT 65.455 79.735 65.785 79.750 ;
      RECT 128.190 80.430 132.085 80.730 ;
      RECT 132.085 80.415 132.415 80.745 ;
      RECT 98.710 81.100 99.090 81.110 ;
      RECT 99.090 81.110 128.190 81.410 ;
      RECT 98.710 81.110 99.090 81.420 ;
      RECT 128.190 80.730 128.490 81.410 ;
      RECT 58.270 80.745 58.570 81.110 ;
      RECT 58.025 80.415 58.355 80.745 ;
      RECT 58.355 80.430 58.570 80.745 ;
      RECT 58.270 81.110 85.625 81.410 ;
      RECT 85.625 81.095 85.955 81.425 ;
      RECT 131.165 81.095 131.495 81.110 ;
      RECT 131.165 81.110 146.550 81.410 ;
      RECT 146.550 81.100 146.930 81.420 ;
      RECT 131.165 81.410 131.495 81.425 ;
      RECT 162.190 81.100 162.570 81.110 ;
      RECT 162.190 81.410 162.570 81.420 ;
      RECT 65.455 80.050 65.785 80.065 ;
      RECT 146.805 80.050 147.135 80.065 ;
      RECT 152.070 80.730 152.450 80.740 ;
      RECT 65.455 79.750 87.925 80.050 ;
      RECT 152.070 80.420 152.450 80.730 ;
      RECT 87.925 79.735 88.255 80.065 ;
      RECT 88.845 79.735 89.175 79.750 ;
      RECT 88.845 80.050 89.175 80.065 ;
      RECT 88.845 79.750 106.785 80.050 ;
      RECT 106.785 79.735 107.115 80.065 ;
      RECT 120.125 79.735 120.455 79.750 ;
      RECT 120.125 80.050 120.455 80.065 ;
      RECT 98.060 81.425 98.360 81.790 ;
      RECT 98.045 81.095 98.375 81.425 ;
      RECT 98.060 81.790 129.110 82.090 ;
      RECT 129.110 81.420 129.410 82.090 ;
      RECT 129.070 81.100 129.450 81.420 ;
      RECT 129.800 81.425 130.100 81.790 ;
      RECT 129.785 81.095 130.115 81.425 ;
      RECT 129.800 81.790 150.500 82.090 ;
      RECT 150.500 81.425 150.800 82.090 ;
      RECT 150.485 81.095 150.815 81.425 ;
      RECT 161.540 81.425 161.840 81.790 ;
      RECT 161.525 81.095 161.855 81.425 ;
      RECT 73.735 80.415 74.065 80.430 ;
      RECT 73.735 80.730 74.065 80.745 ;
      RECT 73.735 80.430 89.305 80.730 ;
      RECT 89.305 80.415 89.635 80.745 ;
      RECT 109.085 80.415 109.415 80.430 ;
      RECT 109.085 80.430 117.110 80.730 ;
      RECT 117.110 80.420 117.490 80.740 ;
      RECT 109.085 80.730 109.415 80.745 ;
      RECT 118.285 80.415 118.615 80.430 ;
      RECT 118.285 80.730 118.615 80.745 ;
      RECT 116.905 2.215 117.235 2.500 ;
      RECT 91.605 1.535 91.935 1.550 ;
      RECT 124.725 1.535 125.055 1.550 ;
      RECT 91.605 1.550 150.230 1.850 ;
      RECT 150.230 1.540 150.610 1.860 ;
      RECT 91.605 1.850 91.935 1.865 ;
      RECT 124.725 1.850 125.055 1.865 ;
      RECT 61.945 0.870 104.025 1.170 ;
      RECT 104.025 0.855 104.355 1.185 ;
      RECT 60.990 2.220 61.370 2.230 ;
      RECT 93.445 2.215 93.775 2.230 ;
      RECT 137.350 2.220 137.730 2.230 ;
      RECT 60.990 2.230 62.245 2.500 ;
      RECT 61.945 1.170 62.245 2.230 ;
      RECT 93.445 2.230 116.905 2.500 ;
      RECT 186.110 2.220 186.490 2.230 ;
      RECT 220.405 2.215 220.735 2.230 ;
      RECT 213.965 0.855 214.295 1.185 ;
      RECT 241.310 1.540 241.690 1.550 ;
      RECT 241.310 1.850 241.690 1.860 ;
      RECT 241.310 1.550 280.870 1.850 ;
      RECT 280.870 1.540 281.250 1.860 ;
      RECT 174.865 2.215 175.195 2.500 ;
      RECT 186.110 2.230 206.605 2.500 ;
      RECT 206.605 2.215 206.935 2.500 ;
      RECT 226.590 0.180 226.970 0.190 ;
      RECT 226.590 0.490 226.970 0.500 ;
      RECT 220.405 2.230 244.990 2.500 ;
      RECT 244.990 2.220 245.370 2.500 ;
      RECT 226.590 0.190 247.750 0.490 ;
      RECT 247.750 0.180 248.130 0.500 ;
      RECT 252.350 0.860 252.730 0.870 ;
      RECT 252.350 1.170 252.730 1.180 ;
      RECT 252.350 0.870 278.110 1.170 ;
      RECT 278.110 0.860 278.490 1.180 ;
      RECT 206.605 0.855 206.935 0.870 ;
      RECT 206.605 1.170 206.935 1.185 ;
      RECT 206.605 0.870 213.965 1.170 ;
    LAYER met4 ;
      RECT 61.015 2.215 61.345 2.500 ;
      RECT 137.375 2.215 137.705 2.500 ;
      RECT 150.270 1.865 150.570 2.500 ;
      RECT 150.255 1.535 150.585 1.865 ;
      RECT 186.135 2.215 186.465 2.500 ;
      RECT 226.630 0.505 226.930 2.500 ;
      RECT 226.615 0.175 226.945 0.505 ;
      RECT 241.350 1.865 241.650 2.500 ;
      RECT 241.335 1.535 241.665 1.865 ;
      RECT 245.015 2.215 245.345 2.500 ;
      RECT 247.790 0.505 248.090 2.500 ;
      RECT 247.775 0.175 248.105 0.505 ;
      RECT 252.390 1.185 252.690 2.500 ;
      RECT 252.375 0.855 252.705 1.185 ;
      RECT 278.150 1.185 278.450 2.500 ;
      RECT 278.135 0.855 278.465 1.185 ;
      RECT 185.215 79.735 185.545 80.065 ;
      RECT 185.230 79.590 185.530 79.735 ;
      RECT 245.935 79.735 246.265 80.065 ;
      RECT 245.950 79.590 246.250 79.735 ;
      RECT 261.575 79.735 261.905 80.065 ;
      RECT 261.590 79.590 261.890 79.735 ;
      RECT 270.775 79.735 271.105 80.065 ;
      RECT 270.790 79.590 271.090 79.735 ;
      RECT 304.815 79.735 305.145 80.065 ;
      RECT 304.830 79.590 305.130 79.735 ;
      RECT 2.500 77.540 327.500 79.590 ;
      RECT 2.340 4.060 327.940 77.540 ;
      RECT 2.500 2.500 327.500 4.060 ;
      RECT 280.910 1.865 281.210 2.500 ;
      RECT 280.895 1.535 281.225 1.865 ;
      RECT 117.135 80.415 117.465 80.745 ;
      RECT 117.150 79.590 117.450 80.415 ;
      RECT 143.815 80.415 144.145 80.745 ;
      RECT 143.830 79.590 144.130 80.415 ;
      RECT 152.095 80.415 152.425 80.745 ;
      RECT 152.110 79.590 152.410 80.415 ;
      RECT 186.135 80.415 186.465 80.745 ;
      RECT 186.150 79.590 186.450 80.415 ;
      RECT 249.615 80.415 249.945 80.745 ;
      RECT 249.630 79.590 249.930 80.415 ;
      RECT 298.375 80.415 298.705 80.745 ;
      RECT 298.390 79.590 298.690 80.415 ;
      RECT 98.735 81.095 99.065 81.425 ;
      RECT 98.750 79.590 99.050 81.095 ;
      RECT 129.095 81.095 129.425 81.425 ;
      RECT 129.410 80.430 142.910 80.730 ;
      RECT 129.110 80.430 129.410 81.095 ;
      RECT 142.910 79.590 143.210 80.730 ;
      RECT 146.575 81.095 146.905 81.425 ;
      RECT 146.590 79.590 146.890 81.095 ;
      RECT 162.215 81.095 162.545 81.425 ;
      RECT 162.230 79.590 162.530 81.095 ;
      RECT 205.455 81.095 205.785 81.425 ;
      RECT 205.470 79.590 205.770 81.095 ;
      RECT 211.895 81.095 212.225 81.425 ;
      RECT 211.910 79.590 212.210 81.095 ;
      RECT 279.055 81.095 279.385 81.425 ;
      RECT 279.070 79.590 279.370 81.095 ;
  END
END rt5w_digital
END LIBRARY
